VERSION 5.8 ;
BUSBITCHARS "[]" ;
DIVIDERCHAR "/" ;
UNITS
    DATABASE MICRONS 1000 ;
END UNITS

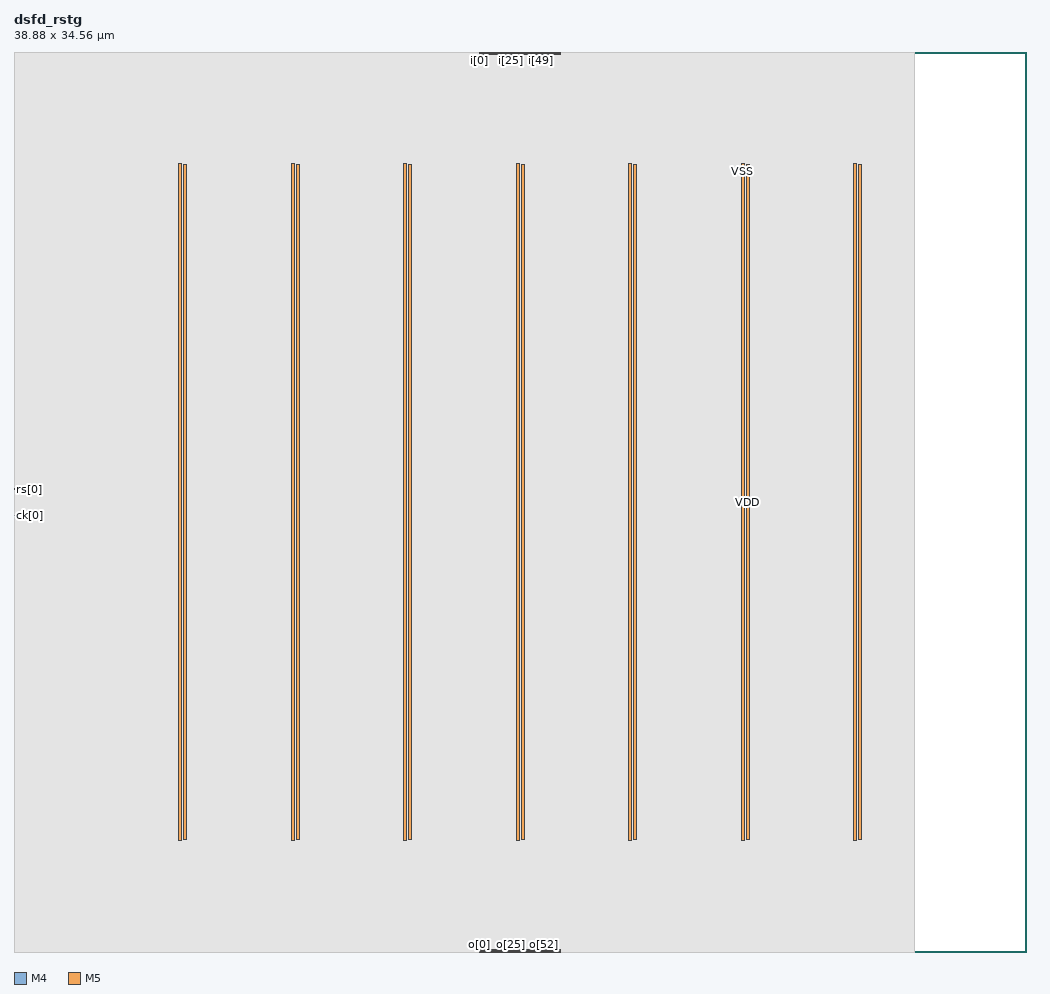
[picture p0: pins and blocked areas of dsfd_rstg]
MACRO dsfd_rstg
  FOREIGN dsfd_rstg 0 0 ;
  CLASS BLOCK ;
  SIZE 38.88 BY 34.56 ;
  PIN ck[0]
    DIRECTION INPUT ;
    USE SIGNAL ;
    PORT
      LAYER M4 ;
        RECT  0 16.752 0.084 16.776 ;
    END
  END ck[0]
  PIN i[0]
    DIRECTION INPUT ;
    USE SIGNAL ;
    PORT
      LAYER M5 ;
        RECT  17.856 34.476 17.88 34.56 ;
    END
  END i[0]
  PIN i[10]
    DIRECTION INPUT ;
    USE SIGNAL ;
    PORT
      LAYER M5 ;
        RECT  18.336 34.476 18.36 34.56 ;
    END
  END i[10]
  PIN i[11]
    DIRECTION INPUT ;
    USE SIGNAL ;
    PORT
      LAYER M5 ;
        RECT  18.384 34.476 18.408 34.56 ;
    END
  END i[11]
  PIN i[12]
    DIRECTION INPUT ;
    USE SIGNAL ;
    PORT
      LAYER M5 ;
        RECT  18.432 34.476 18.456 34.56 ;
    END
  END i[12]
  PIN i[13]
    DIRECTION INPUT ;
    USE SIGNAL ;
    PORT
      LAYER M5 ;
        RECT  18.48 34.476 18.504 34.56 ;
    END
  END i[13]
  PIN i[14]
    DIRECTION INPUT ;
    USE SIGNAL ;
    PORT
      LAYER M5 ;
        RECT  18.528 34.476 18.552 34.56 ;
    END
  END i[14]
  PIN i[15]
    DIRECTION INPUT ;
    USE SIGNAL ;
    PORT
      LAYER M5 ;
        RECT  18.576 34.476 18.6 34.56 ;
    END
  END i[15]
  PIN i[16]
    DIRECTION INPUT ;
    USE SIGNAL ;
    PORT
      LAYER M5 ;
        RECT  18.624 34.476 18.648 34.56 ;
    END
  END i[16]
  PIN i[17]
    DIRECTION INPUT ;
    USE SIGNAL ;
    PORT
      LAYER M5 ;
        RECT  18.672 34.476 18.696 34.56 ;
    END
  END i[17]
  PIN i[18]
    DIRECTION INPUT ;
    USE SIGNAL ;
    PORT
      LAYER M5 ;
        RECT  18.72 34.476 18.744 34.56 ;
    END
  END i[18]
  PIN i[19]
    DIRECTION INPUT ;
    USE SIGNAL ;
    PORT
      LAYER M5 ;
        RECT  18.768 34.476 18.792 34.56 ;
    END
  END i[19]
  PIN i[1]
    DIRECTION INPUT ;
    USE SIGNAL ;
    PORT
      LAYER M5 ;
        RECT  17.904 34.476 17.928 34.56 ;
    END
  END i[1]
  PIN i[20]
    DIRECTION INPUT ;
    USE SIGNAL ;
    PORT
      LAYER M5 ;
        RECT  18.816 34.476 18.84 34.56 ;
    END
  END i[20]
  PIN i[21]
    DIRECTION INPUT ;
    USE SIGNAL ;
    PORT
      LAYER M5 ;
        RECT  18.864 34.476 18.888 34.56 ;
    END
  END i[21]
  PIN i[22]
    DIRECTION INPUT ;
    USE SIGNAL ;
    PORT
      LAYER M5 ;
        RECT  18.912 34.476 18.936 34.56 ;
    END
  END i[22]
  PIN i[23]
    DIRECTION INPUT ;
    USE SIGNAL ;
    PORT
      LAYER M5 ;
        RECT  18.96 34.476 18.984 34.56 ;
    END
  END i[23]
  PIN i[24]
    DIRECTION INPUT ;
    USE SIGNAL ;
    PORT
      LAYER M5 ;
        RECT  19.008 34.476 19.032 34.56 ;
    END
  END i[24]
  PIN i[25]
    DIRECTION INPUT ;
    USE SIGNAL ;
    PORT
      LAYER M5 ;
        RECT  19.056 34.476 19.08 34.56 ;
    END
  END i[25]
  PIN i[26]
    DIRECTION INPUT ;
    USE SIGNAL ;
    PORT
      LAYER M5 ;
        RECT  19.104 34.476 19.128 34.56 ;
    END
  END i[26]
  PIN i[27]
    DIRECTION INPUT ;
    USE SIGNAL ;
    PORT
      LAYER M5 ;
        RECT  19.152 34.476 19.176 34.56 ;
    END
  END i[27]
  PIN i[28]
    DIRECTION INPUT ;
    USE SIGNAL ;
    PORT
      LAYER M5 ;
        RECT  19.2 34.476 19.224 34.56 ;
    END
  END i[28]
  PIN i[29]
    DIRECTION INPUT ;
    USE SIGNAL ;
    PORT
      LAYER M5 ;
        RECT  19.248 34.476 19.272 34.56 ;
    END
  END i[29]
  PIN i[2]
    DIRECTION INPUT ;
    USE SIGNAL ;
    PORT
      LAYER M5 ;
        RECT  17.952 34.476 17.976 34.56 ;
    END
  END i[2]
  PIN i[30]
    DIRECTION INPUT ;
    USE SIGNAL ;
    PORT
      LAYER M5 ;
        RECT  19.296 34.476 19.32 34.56 ;
    END
  END i[30]
  PIN i[31]
    DIRECTION INPUT ;
    USE SIGNAL ;
    PORT
      LAYER M5 ;
        RECT  19.344 34.476 19.368 34.56 ;
    END
  END i[31]
  PIN i[32]
    DIRECTION INPUT ;
    USE SIGNAL ;
    PORT
      LAYER M5 ;
        RECT  19.392 34.476 19.416 34.56 ;
    END
  END i[32]
  PIN i[33]
    DIRECTION INPUT ;
    USE SIGNAL ;
    PORT
      LAYER M5 ;
        RECT  19.44 34.476 19.464 34.56 ;
    END
  END i[33]
  PIN i[34]
    DIRECTION INPUT ;
    USE SIGNAL ;
    PORT
      LAYER M5 ;
        RECT  19.488 34.476 19.512 34.56 ;
    END
  END i[34]
  PIN i[35]
    DIRECTION INPUT ;
    USE SIGNAL ;
    PORT
      LAYER M5 ;
        RECT  19.536 34.476 19.56 34.56 ;
    END
  END i[35]
  PIN i[36]
    DIRECTION INPUT ;
    USE SIGNAL ;
    PORT
      LAYER M5 ;
        RECT  19.584 34.476 19.608 34.56 ;
    END
  END i[36]
  PIN i[37]
    DIRECTION INPUT ;
    USE SIGNAL ;
    PORT
      LAYER M5 ;
        RECT  19.632 34.476 19.656 34.56 ;
    END
  END i[37]
  PIN i[38]
    DIRECTION INPUT ;
    USE SIGNAL ;
    PORT
      LAYER M5 ;
        RECT  19.68 34.476 19.704 34.56 ;
    END
  END i[38]
  PIN i[39]
    DIRECTION INPUT ;
    USE SIGNAL ;
    PORT
      LAYER M5 ;
        RECT  19.728 34.476 19.752 34.56 ;
    END
  END i[39]
  PIN i[3]
    DIRECTION INPUT ;
    USE SIGNAL ;
    PORT
      LAYER M5 ;
        RECT  18 34.476 18.024 34.56 ;
    END
  END i[3]
  PIN i[40]
    DIRECTION INPUT ;
    USE SIGNAL ;
    PORT
      LAYER M5 ;
        RECT  19.776 34.476 19.8 34.56 ;
    END
  END i[40]
  PIN i[41]
    DIRECTION INPUT ;
    USE SIGNAL ;
    PORT
      LAYER M5 ;
        RECT  19.824 34.476 19.848 34.56 ;
    END
  END i[41]
  PIN i[42]
    DIRECTION INPUT ;
    USE SIGNAL ;
    PORT
      LAYER M5 ;
        RECT  19.872 34.476 19.896 34.56 ;
    END
  END i[42]
  PIN i[43]
    DIRECTION INPUT ;
    USE SIGNAL ;
    PORT
      LAYER M5 ;
        RECT  19.92 34.476 19.944 34.56 ;
    END
  END i[43]
  PIN i[44]
    DIRECTION INPUT ;
    USE SIGNAL ;
    PORT
      LAYER M5 ;
        RECT  19.968 34.476 19.992 34.56 ;
    END
  END i[44]
  PIN i[45]
    DIRECTION INPUT ;
    USE SIGNAL ;
    PORT
      LAYER M5 ;
        RECT  20.016 34.476 20.04 34.56 ;
    END
  END i[45]
  PIN i[46]
    DIRECTION INPUT ;
    USE SIGNAL ;
    PORT
      LAYER M5 ;
        RECT  20.064 34.476 20.088 34.56 ;
    END
  END i[46]
  PIN i[47]
    DIRECTION INPUT ;
    USE SIGNAL ;
    PORT
      LAYER M5 ;
        RECT  20.112 34.476 20.136 34.56 ;
    END
  END i[47]
  PIN i[48]
    DIRECTION INPUT ;
    USE SIGNAL ;
    PORT
      LAYER M5 ;
        RECT  20.16 34.476 20.184 34.56 ;
    END
  END i[48]
  PIN i[49]
    DIRECTION INPUT ;
    USE SIGNAL ;
    PORT
      LAYER M5 ;
        RECT  20.208 34.476 20.232 34.56 ;
    END
  END i[49]
  PIN i[4]
    DIRECTION INPUT ;
    USE SIGNAL ;
    PORT
      LAYER M5 ;
        RECT  18.048 34.476 18.072 34.56 ;
    END
  END i[4]
  PIN i[50]
    DIRECTION INPUT ;
    USE SIGNAL ;
    PORT
      LAYER M5 ;
        RECT  20.256 34.476 20.28 34.56 ;
    END
  END i[50]
  PIN i[51]
    DIRECTION INPUT ;
    USE SIGNAL ;
    PORT
      LAYER M5 ;
        RECT  20.304 34.476 20.328 34.56 ;
    END
  END i[51]
  PIN i[52]
    DIRECTION INPUT ;
    USE SIGNAL ;
    PORT
      LAYER M5 ;
        RECT  20.352 34.476 20.376 34.56 ;
    END
  END i[52]
  PIN i[53]
    DIRECTION INPUT ;
    USE SIGNAL ;
    PORT
      LAYER M5 ;
        RECT  20.4 34.476 20.424 34.56 ;
    END
  END i[53]
  PIN i[54]
    DIRECTION INPUT ;
    USE SIGNAL ;
    PORT
      LAYER M5 ;
        RECT  20.448 34.476 20.472 34.56 ;
    END
  END i[54]
  PIN i[55]
    DIRECTION INPUT ;
    USE SIGNAL ;
    PORT
      LAYER M5 ;
        RECT  20.496 34.476 20.52 34.56 ;
    END
  END i[55]
  PIN i[56]
    DIRECTION INPUT ;
    USE SIGNAL ;
    PORT
      LAYER M5 ;
        RECT  20.544 34.476 20.568 34.56 ;
    END
  END i[56]
  PIN i[57]
    DIRECTION INPUT ;
    USE SIGNAL ;
    PORT
      LAYER M5 ;
        RECT  20.592 34.476 20.616 34.56 ;
    END
  END i[57]
  PIN i[58]
    DIRECTION INPUT ;
    USE SIGNAL ;
    PORT
      LAYER M5 ;
        RECT  20.64 34.476 20.664 34.56 ;
    END
  END i[58]
  PIN i[59]
    DIRECTION INPUT ;
    USE SIGNAL ;
    PORT
      LAYER M5 ;
        RECT  20.688 34.476 20.712 34.56 ;
    END
  END i[59]
  PIN i[5]
    DIRECTION INPUT ;
    USE SIGNAL ;
    PORT
      LAYER M5 ;
        RECT  18.096 34.476 18.12 34.56 ;
    END
  END i[5]
  PIN i[60]
    DIRECTION INPUT ;
    USE SIGNAL ;
    PORT
      LAYER M5 ;
        RECT  20.736 34.476 20.76 34.56 ;
    END
  END i[60]
  PIN i[61]
    DIRECTION INPUT ;
    USE SIGNAL ;
    PORT
      LAYER M5 ;
        RECT  20.784 34.476 20.808 34.56 ;
    END
  END i[61]
  PIN i[62]
    DIRECTION INPUT ;
    USE SIGNAL ;
    PORT
      LAYER M5 ;
        RECT  20.832 34.476 20.856 34.56 ;
    END
  END i[62]
  PIN i[63]
    DIRECTION INPUT ;
    USE SIGNAL ;
    PORT
      LAYER M5 ;
        RECT  20.88 34.476 20.904 34.56 ;
    END
  END i[63]
  PIN i[64]
    DIRECTION INPUT ;
    USE SIGNAL ;
    PORT
      LAYER M5 ;
        RECT  20.928 34.476 20.952 34.56 ;
    END
  END i[64]
  PIN i[65]
    DIRECTION INPUT ;
    USE SIGNAL ;
    PORT
      LAYER M5 ;
        RECT  20.976 34.476 21 34.56 ;
    END
  END i[65]
  PIN i[6]
    DIRECTION INPUT ;
    USE SIGNAL ;
    PORT
      LAYER M5 ;
        RECT  18.144 34.476 18.168 34.56 ;
    END
  END i[6]
  PIN i[7]
    DIRECTION INPUT ;
    USE SIGNAL ;
    PORT
      LAYER M5 ;
        RECT  18.192 34.476 18.216 34.56 ;
    END
  END i[7]
  PIN i[8]
    DIRECTION INPUT ;
    USE SIGNAL ;
    PORT
      LAYER M5 ;
        RECT  18.24 34.476 18.264 34.56 ;
    END
  END i[8]
  PIN i[9]
    DIRECTION INPUT ;
    USE SIGNAL ;
    PORT
      LAYER M5 ;
        RECT  18.288 34.476 18.312 34.56 ;
    END
  END i[9]
  PIN o[0]
    DIRECTION OUTPUT ;
    USE SIGNAL ;
    PORT
      LAYER M5 ;
        RECT  17.856 0 17.88 0.084 ;
    END
  END o[0]
  PIN o[10]
    DIRECTION OUTPUT ;
    USE SIGNAL ;
    PORT
      LAYER M5 ;
        RECT  18.336 0 18.36 0.084 ;
    END
  END o[10]
  PIN o[11]
    DIRECTION OUTPUT ;
    USE SIGNAL ;
    PORT
      LAYER M5 ;
        RECT  18.384 0 18.408 0.084 ;
    END
  END o[11]
  PIN o[12]
    DIRECTION OUTPUT ;
    USE SIGNAL ;
    PORT
      LAYER M5 ;
        RECT  18.432 0 18.456 0.084 ;
    END
  END o[12]
  PIN o[13]
    DIRECTION OUTPUT ;
    USE SIGNAL ;
    PORT
      LAYER M5 ;
        RECT  18.48 0 18.504 0.084 ;
    END
  END o[13]
  PIN o[14]
    DIRECTION OUTPUT ;
    USE SIGNAL ;
    PORT
      LAYER M5 ;
        RECT  18.528 0 18.552 0.084 ;
    END
  END o[14]
  PIN o[15]
    DIRECTION OUTPUT ;
    USE SIGNAL ;
    PORT
      LAYER M5 ;
        RECT  18.576 0 18.6 0.084 ;
    END
  END o[15]
  PIN o[16]
    DIRECTION OUTPUT ;
    USE SIGNAL ;
    PORT
      LAYER M5 ;
        RECT  18.624 0 18.648 0.084 ;
    END
  END o[16]
  PIN o[17]
    DIRECTION OUTPUT ;
    USE SIGNAL ;
    PORT
      LAYER M5 ;
        RECT  18.672 0 18.696 0.084 ;
    END
  END o[17]
  PIN o[18]
    DIRECTION OUTPUT ;
    USE SIGNAL ;
    PORT
      LAYER M5 ;
        RECT  18.72 0 18.744 0.084 ;
    END
  END o[18]
  PIN o[19]
    DIRECTION OUTPUT ;
    USE SIGNAL ;
    PORT
      LAYER M5 ;
        RECT  18.768 0 18.792 0.084 ;
    END
  END o[19]
  PIN o[1]
    DIRECTION OUTPUT ;
    USE SIGNAL ;
    PORT
      LAYER M5 ;
        RECT  17.904 0 17.928 0.084 ;
    END
  END o[1]
  PIN o[20]
    DIRECTION OUTPUT ;
    USE SIGNAL ;
    PORT
      LAYER M5 ;
        RECT  18.816 0 18.84 0.084 ;
    END
  END o[20]
  PIN o[21]
    DIRECTION OUTPUT ;
    USE SIGNAL ;
    PORT
      LAYER M5 ;
        RECT  18.864 0 18.888 0.084 ;
    END
  END o[21]
  PIN o[22]
    DIRECTION OUTPUT ;
    USE SIGNAL ;
    PORT
      LAYER M5 ;
        RECT  18.912 0 18.936 0.084 ;
    END
  END o[22]
  PIN o[23]
    DIRECTION OUTPUT ;
    USE SIGNAL ;
    PORT
      LAYER M5 ;
        RECT  18.96 0 18.984 0.084 ;
    END
  END o[23]
  PIN o[24]
    DIRECTION OUTPUT ;
    USE SIGNAL ;
    PORT
      LAYER M5 ;
        RECT  19.008 0 19.032 0.084 ;
    END
  END o[24]
  PIN o[25]
    DIRECTION OUTPUT ;
    USE SIGNAL ;
    PORT
      LAYER M5 ;
        RECT  19.056 0 19.08 0.084 ;
    END
  END o[25]
  PIN o[26]
    DIRECTION OUTPUT ;
    USE SIGNAL ;
    PORT
      LAYER M5 ;
        RECT  19.104 0 19.128 0.084 ;
    END
  END o[26]
  PIN o[27]
    DIRECTION OUTPUT ;
    USE SIGNAL ;
    PORT
      LAYER M5 ;
        RECT  19.152 0 19.176 0.084 ;
    END
  END o[27]
  PIN o[28]
    DIRECTION OUTPUT ;
    USE SIGNAL ;
    PORT
      LAYER M5 ;
        RECT  19.2 0 19.224 0.084 ;
    END
  END o[28]
  PIN o[29]
    DIRECTION OUTPUT ;
    USE SIGNAL ;
    PORT
      LAYER M5 ;
        RECT  19.248 0 19.272 0.084 ;
    END
  END o[29]
  PIN o[2]
    DIRECTION OUTPUT ;
    USE SIGNAL ;
    PORT
      LAYER M5 ;
        RECT  17.952 0 17.976 0.084 ;
    END
  END o[2]
  PIN o[30]
    DIRECTION OUTPUT ;
    USE SIGNAL ;
    PORT
      LAYER M5 ;
        RECT  19.296 0 19.32 0.084 ;
    END
  END o[30]
  PIN o[31]
    DIRECTION OUTPUT ;
    USE SIGNAL ;
    PORT
      LAYER M5 ;
        RECT  19.344 0 19.368 0.084 ;
    END
  END o[31]
  PIN o[32]
    DIRECTION OUTPUT ;
    USE SIGNAL ;
    PORT
      LAYER M5 ;
        RECT  19.392 0 19.416 0.084 ;
    END
  END o[32]
  PIN o[33]
    DIRECTION OUTPUT ;
    USE SIGNAL ;
    PORT
      LAYER M5 ;
        RECT  19.44 0 19.464 0.084 ;
    END
  END o[33]
  PIN o[34]
    DIRECTION OUTPUT ;
    USE SIGNAL ;
    PORT
      LAYER M5 ;
        RECT  19.488 0 19.512 0.084 ;
    END
  END o[34]
  PIN o[35]
    DIRECTION OUTPUT ;
    USE SIGNAL ;
    PORT
      LAYER M5 ;
        RECT  19.536 0 19.56 0.084 ;
    END
  END o[35]
  PIN o[36]
    DIRECTION OUTPUT ;
    USE SIGNAL ;
    PORT
      LAYER M5 ;
        RECT  19.584 0 19.608 0.084 ;
    END
  END o[36]
  PIN o[37]
    DIRECTION OUTPUT ;
    USE SIGNAL ;
    PORT
      LAYER M5 ;
        RECT  19.632 0 19.656 0.084 ;
    END
  END o[37]
  PIN o[38]
    DIRECTION OUTPUT ;
    USE SIGNAL ;
    PORT
      LAYER M5 ;
        RECT  19.68 0 19.704 0.084 ;
    END
  END o[38]
  PIN o[39]
    DIRECTION OUTPUT ;
    USE SIGNAL ;
    PORT
      LAYER M5 ;
        RECT  19.728 0 19.752 0.084 ;
    END
  END o[39]
  PIN o[3]
    DIRECTION OUTPUT ;
    USE SIGNAL ;
    PORT
      LAYER M5 ;
        RECT  18 0 18.024 0.084 ;
    END
  END o[3]
  PIN o[40]
    DIRECTION OUTPUT ;
    USE SIGNAL ;
    PORT
      LAYER M5 ;
        RECT  19.776 0 19.8 0.084 ;
    END
  END o[40]
  PIN o[41]
    DIRECTION OUTPUT ;
    USE SIGNAL ;
    PORT
      LAYER M5 ;
        RECT  19.824 0 19.848 0.084 ;
    END
  END o[41]
  PIN o[42]
    DIRECTION OUTPUT ;
    USE SIGNAL ;
    PORT
      LAYER M5 ;
        RECT  19.872 0 19.896 0.084 ;
    END
  END o[42]
  PIN o[43]
    DIRECTION OUTPUT ;
    USE SIGNAL ;
    PORT
      LAYER M5 ;
        RECT  19.92 0 19.944 0.084 ;
    END
  END o[43]
  PIN o[44]
    DIRECTION OUTPUT ;
    USE SIGNAL ;
    PORT
      LAYER M5 ;
        RECT  19.968 0 19.992 0.084 ;
    END
  END o[44]
  PIN o[45]
    DIRECTION OUTPUT ;
    USE SIGNAL ;
    PORT
      LAYER M5 ;
        RECT  20.016 0 20.04 0.084 ;
    END
  END o[45]
  PIN o[46]
    DIRECTION OUTPUT ;
    USE SIGNAL ;
    PORT
      LAYER M5 ;
        RECT  20.064 0 20.088 0.084 ;
    END
  END o[46]
  PIN o[47]
    DIRECTION OUTPUT ;
    USE SIGNAL ;
    PORT
      LAYER M5 ;
        RECT  20.112 0 20.136 0.084 ;
    END
  END o[47]
  PIN o[48]
    DIRECTION OUTPUT ;
    USE SIGNAL ;
    PORT
      LAYER M5 ;
        RECT  20.16 0 20.184 0.084 ;
    END
  END o[48]
  PIN o[49]
    DIRECTION OUTPUT ;
    USE SIGNAL ;
    PORT
      LAYER M5 ;
        RECT  20.208 0 20.232 0.084 ;
    END
  END o[49]
  PIN o[4]
    DIRECTION OUTPUT ;
    USE SIGNAL ;
    PORT
      LAYER M5 ;
        RECT  18.048 0 18.072 0.084 ;
    END
  END o[4]
  PIN o[50]
    DIRECTION OUTPUT ;
    USE SIGNAL ;
    PORT
      LAYER M5 ;
        RECT  20.256 0 20.28 0.084 ;
    END
  END o[50]
  PIN o[51]
    DIRECTION OUTPUT ;
    USE SIGNAL ;
    PORT
      LAYER M5 ;
        RECT  20.304 0 20.328 0.084 ;
    END
  END o[51]
  PIN o[52]
    DIRECTION OUTPUT ;
    USE SIGNAL ;
    PORT
      LAYER M5 ;
        RECT  20.352 0 20.376 0.084 ;
    END
  END o[52]
  PIN o[53]
    DIRECTION OUTPUT ;
    USE SIGNAL ;
    PORT
      LAYER M5 ;
        RECT  20.4 0 20.424 0.084 ;
    END
  END o[53]
  PIN o[54]
    DIRECTION OUTPUT ;
    USE SIGNAL ;
    PORT
      LAYER M5 ;
        RECT  20.448 0 20.472 0.084 ;
    END
  END o[54]
  PIN o[55]
    DIRECTION OUTPUT ;
    USE SIGNAL ;
    PORT
      LAYER M5 ;
        RECT  20.496 0 20.52 0.084 ;
    END
  END o[55]
  PIN o[56]
    DIRECTION OUTPUT ;
    USE SIGNAL ;
    PORT
      LAYER M5 ;
        RECT  20.544 0 20.568 0.084 ;
    END
  END o[56]
  PIN o[57]
    DIRECTION OUTPUT ;
    USE SIGNAL ;
    PORT
      LAYER M5 ;
        RECT  20.592 0 20.616 0.084 ;
    END
  END o[57]
  PIN o[58]
    DIRECTION OUTPUT ;
    USE SIGNAL ;
    PORT
      LAYER M5 ;
        RECT  20.64 0 20.664 0.084 ;
    END
  END o[58]
  PIN o[59]
    DIRECTION OUTPUT ;
    USE SIGNAL ;
    PORT
      LAYER M5 ;
        RECT  20.688 0 20.712 0.084 ;
    END
  END o[59]
  PIN o[5]
    DIRECTION OUTPUT ;
    USE SIGNAL ;
    PORT
      LAYER M5 ;
        RECT  18.096 0 18.12 0.084 ;
    END
  END o[5]
  PIN o[60]
    DIRECTION OUTPUT ;
    USE SIGNAL ;
    PORT
      LAYER M5 ;
        RECT  20.736 0 20.76 0.084 ;
    END
  END o[60]
  PIN o[61]
    DIRECTION OUTPUT ;
    USE SIGNAL ;
    PORT
      LAYER M5 ;
        RECT  20.784 0 20.808 0.084 ;
    END
  END o[61]
  PIN o[62]
    DIRECTION OUTPUT ;
    USE SIGNAL ;
    PORT
      LAYER M5 ;
        RECT  20.832 0 20.856 0.084 ;
    END
  END o[62]
  PIN o[63]
    DIRECTION OUTPUT ;
    USE SIGNAL ;
    PORT
      LAYER M5 ;
        RECT  20.88 0 20.904 0.084 ;
    END
  END o[63]
  PIN o[64]
    DIRECTION OUTPUT ;
    USE SIGNAL ;
    PORT
      LAYER M5 ;
        RECT  20.928 0 20.952 0.084 ;
    END
  END o[64]
  PIN o[65]
    DIRECTION OUTPUT ;
    USE SIGNAL ;
    PORT
      LAYER M5 ;
        RECT  20.976 0 21 0.084 ;
    END
  END o[65]
  PIN o[6]
    DIRECTION OUTPUT ;
    USE SIGNAL ;
    PORT
      LAYER M5 ;
        RECT  18.144 0 18.168 0.084 ;
    END
  END o[6]
  PIN o[7]
    DIRECTION OUTPUT ;
    USE SIGNAL ;
    PORT
      LAYER M5 ;
        RECT  18.192 0 18.216 0.084 ;
    END
  END o[7]
  PIN o[8]
    DIRECTION OUTPUT ;
    USE SIGNAL ;
    PORT
      LAYER M5 ;
        RECT  18.24 0 18.264 0.084 ;
    END
  END o[8]
  PIN o[9]
    DIRECTION OUTPUT ;
    USE SIGNAL ;
    PORT
      LAYER M5 ;
        RECT  18.288 0 18.312 0.084 ;
    END
  END o[9]
  PIN rs[0]
    DIRECTION INPUT ;
    USE SIGNAL ;
    PORT
      LAYER M4 ;
        RECT  0 17.76 0.084 17.784 ;
    END
  END rs[0]
  PIN VDD
    DIRECTION INOUT ;
    USE POWER ;
    PORT
      LAYER M5 ;
        RECT  32.436 4.311 32.556 30.249 ;
        RECT  28.116 4.311 28.236 30.249 ;
        RECT  23.796 4.311 23.916 30.249 ;
        RECT  19.476 4.311 19.596 30.249 ;
        RECT  15.156 4.311 15.276 30.249 ;
        RECT  10.836 4.311 10.956 30.249 ;
        RECT  6.516 4.311 6.636 30.249 ;
    END
  END VDD
  PIN VSS
    DIRECTION INOUT ;
    USE GROUND ;
    PORT
      LAYER M5 ;
        RECT  32.244 4.297 32.364 30.263 ;
        RECT  27.924 4.297 28.044 30.263 ;
        RECT  23.604 4.297 23.724 30.263 ;
        RECT  19.284 4.297 19.404 30.263 ;
        RECT  14.964 4.297 15.084 30.263 ;
        RECT  10.644 4.297 10.764 30.263 ;
        RECT  6.324 4.297 6.444 30.263 ;
    END
  END VSS
  OBS
    LAYER RVTN ;
     RECT  0 0 34.56 34.56 ;
    LAYER RVTP ;
     RECT  0 0 34.56 34.56 ;
    LAYER M1 ;
     RECT  0 0 34.56 34.56 ;
    LAYER M2 ;
     RECT  0 0 34.56 34.56 ;
    LAYER M3 ;
     RECT  0 0 34.56 34.56 ;
    LAYER M4 ;
     RECT  0 0 34.56 34.56 ;
    LAYER M5 ;
     RECT  0 0 34.56 34.56 ;
  END
END dsfd_rstg
END LIBRARY
